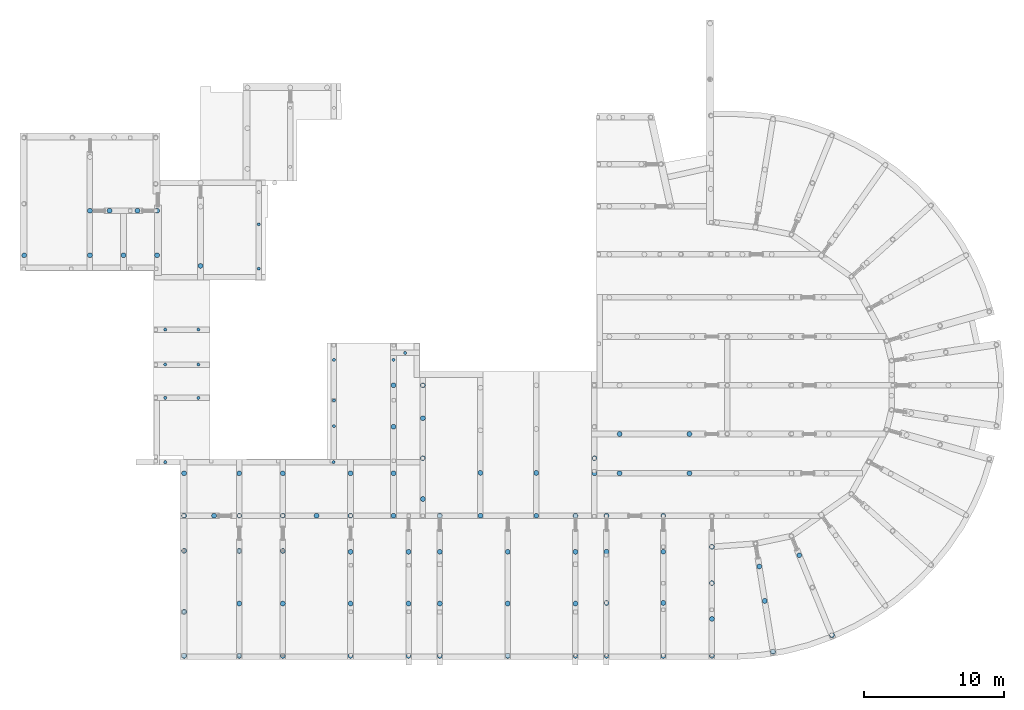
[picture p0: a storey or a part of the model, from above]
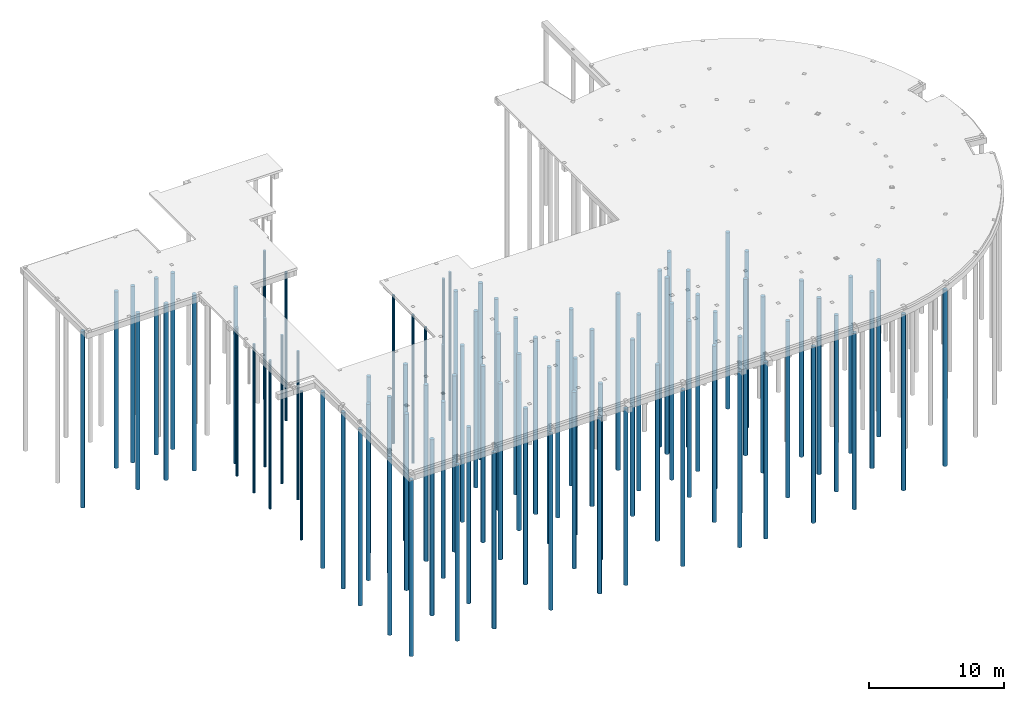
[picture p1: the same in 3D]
Properties of the parts of a building model (IFC2X3)

# File
Description: ViewDefinition[CoordinationView_V2.0, QuantityTakeOffAddOnView], Option [BaseQuantities:On], Option [GridExport:Off], Option [Assemblies:Off], Option [Bolts:On], Option [Rebars:On], Option [PourObjects:Off], Option [Welds:On], Option [SurfaceTreatments:On], Option [LocationBy:0], Option [ViewColors:On], Option [SectionedSpine:Off], Option [PropertySets:On], Option [Export all:Off]
File name: 8694 IFC Fundering revA 17-03-2023.ifc
Time: 2023-03-17T07:30:23
Author: IMJ\s.sijsma
Organization: Structural Designer
Written by: IFC Parser Version: 3.13.2
Made in: Tekla Structures 2022 Service Pack 4, IFC Export Version: 4.0.0.0 Aug 24 2022

# IfcProject, Undefined
BIM Basis ILS - IFC_BUILDING_STOREY: Undefined

# IfcBuildingStorey, Undefined
In: Undefined
Elevation: 0 mm

# IfcBeam: 400*500 (79)
In: Undefined
Description: 400*500; Material: CONCRETE/C30/37
BIM Basis ILS - IS_EXTERNAL: Nee; LOAD_BEARING: Nee; IFC_ENTITY: Auto
Default - MATERIAL: C30/37; NAME: BALK
Tekla Common - Bottom elevation: -0.770; Top elevation: -0.270; Phase: 200; Class: 8
Tekla Quantity - Height: 500 mm; Width: 400 mm
Pset_BeamCommon - IsExternal: no; LoadBearing: no; Reference: BB00(?)
Name | Weight (kg) | Volume (m3) | Gross footprint area (m2) | Area per tons (m2) | Net surface area (m2) | Tekla Quantity, Length (mm) | BaseQuantities, Length (mm) | OuterSurfaceArea (m2) | NetVolume (m3) | NetWeight (kg)
BALK | 2401.81 | 1.001 | 2.002 | 3.917 | 9.407 | 5003.8 | 5003.77 | 9.40679 | 1.00075 | 2401.81
BALK | 3215.83 | 1.34 | 2.68 | 3.874 | 12.459 | 6699.6 | 6699.64 | 12.4594 | 1.33993 | 3215.83
BALK | 2153.51 | 0.897 | 1.795 | 3.936 | 8.476 | 4486.5 | 4486.47 | 8.47565 | 0.897294 | 2153.51
2 x BALK | 816.33 | 0.34 | 0.68 | 4.241 | 3.462 | 1725.6 | 1725.63 | 3.46203 | 0.340139 | 816.334
BALK | 11942.2 | 4.976 | 9.952 | 3.784 | 45.184 | 24886.4 | 24886.4 | 45.1835 | 4.97594 | 11942.2
BALK | 12793 | 5.33 | 10.661 | 3.781 | 48.374 | 26658.8 | 26658.8 | 48.3738 | 5.33041 | 12793
BALK | 1714.9 | 0.715 | 1.429 | 3.983 | 6.831 | 3572.7 | 3572.71 | 6.83088 | 0.714542 | 1714.9
BALK | 2044.02 | 0.852 | 1.703 | 3.946 | 8.065 | 4258.4 | 4258.38 | 8.06508 | 0.851676 | 2044.02
BALK | 7235.25 | 3.015 | 6.029 | 3.805 | 27.532 | 15073.4 | 15073.4 | 27.5322 | 3.01469 | 7235.25
BALK | 7056.49 | 2.94 | 5.88 | 3.807 | 26.862 | 14701 | 14701 | 26.8618 | 2.94021 | 7056.49
BALK | 2963.76 | 1.235 | 2.47 | 3.885 | 11.514 | 6174.5 | 6174.49 | 11.5141 | 1.2349 | 2963.76
2 x BALK | 2963.56 | 1.235 | 2.47 | 3.885 | 11.513 | 6174.1 | 6174.09 | 11.5134 | 1.23482 | 2963.56
BALK | 5294.5 | 2.206 | 4.412 | 3.826 | 20.254 | 11030.2 | 11030.2 | 20.2544 | 2.20604 | 5294.5
2 x BALK | 3940.48 | 1.642 | 3.284 | 3.852 | 15.177 | 8209.3 | 8209.33 | 15.1768 | 1.64187 | 3940.48
BALK | 3761.73 | 1.567 | 3.135 | 3.856 | 14.506 | 7836.9 | 7836.94 | 14.5065 | 1.56739 | 3761.73
BALK | 3542.72 | 1.476 | 2.952 | 3.863 | 13.685 | 7380.7 | 7380.67 | 13.6852 | 1.47613 | 3542.72
BALK | 6171.96 | 2.572 | 5.143 | 3.815 | 23.545 | 12858.3 | 12858.3 | 23.5449 | 2.57165 | 6171.96
BALK | 2832.2 | 1.18 | 2.36 | 3.891 | 11.021 | 5900.4 | 5900.41 | 11.0207 | 1.18008 | 2832.2
3 x BALK | 2345.29 | 0.977 | 1.954 | 3.921 | 9.195 | 4886 | 4886.02 | 9.19483 | 0.977203 | 2345.29
BALK | 13706 | 5.711 | 11.422 | 3.779 | 51.798 | 28554.2 | 28554.2 | 51.7975 | 5.71083 | 13706
BALK | 1347.88 | 0.562 | 1.123 | 4.047 | 5.455 | 2808.1 | 2808.08 | 5.45454 | 0.561616 | 1347.88
BALK | 996.89 | 0.415 | 0.831 | 4.151 | 4.138 | 2076.9 | 2076.85 | 4.13834 | 0.415371 | 996.89
BALK | 1166.15 | 0.486 | 0.972 | 4.093 | 4.773 | 2429.5 | 2429.48 | 4.77306 | 0.485895 | 1166.15
BALK | 2363.52 | 0.985 | 1.97 | 3.919 | 9.263 | 4924 | 4923.99 | 9.26318 | 0.984798 | 2363.52
BALK | 4097.51 | 1.707 | 3.415 | 3.848 | 15.766 | 8536.5 | 8536.47 | 15.7656 | 1.70729 | 4097.51
BALK | 1230.9 | 0.513 | 1.026 | 4.075 | 5.016 | 2564.4 | 2564.37 | 5.01586 | 0.512873 | 1230.9
BALK | 2724.78 | 1.135 | 2.271 | 3.897 | 10.618 | 5676.6 | 5676.62 | 10.6179 | 1.13532 | 2724.78
BALK | 4855.85 | 2.023 | 4.047 | 3.832 | 18.609 | 10116.4 | 10116.4 | 18.6094 | 2.02327 | 4855.85
BALK | 3869.92 | 1.612 | 3.225 | 3.853 | 14.912 | 8062.3 | 8062.34 | 14.9122 | 1.61247 | 3869.92
BALK | 3399.12 | 1.416 | 2.833 | 3.868 | 13.147 | 7081.5 | 7081.51 | 13.1467 | 1.4163 | 3399.12
BALK | 2856.74 | 1.19 | 2.381 | 3.891 | 11.113 | 5951.5 | 5951.53 | 11.1128 | 1.19031 | 2856.74
BALK | 3815.86 | 1.59 | 3.18 | 3.856 | 14.709 | 7949.7 | 7949.72 | 14.7095 | 1.58994 | 3815.86
2 x BALK | 1905.59 | 0.794 | 1.588 | 3.96 | 7.546 | 3970 | 3969.97 | 7.54595 | 0.793994 | 1905.59
BALK | 1908.71 | 0.795 | 1.591 | 3.96 | 7.558 | 3976.5 | 3976.47 | 7.55765 | 0.795294 | 1908.71
BALK | 9965.13 | 4.152 | 8.304 | 3.79 | 37.769 | 20760.7 | 20760.7 | 37.7693 | 4.15214 | 9965.13
BALK | 3988.27 | 1.662 | 3.324 | 3.85 | 15.356 | 8308.9 | 8308.89 | 15.356 | 1.66178 | 3988.27
4 x BALK | 5046.09 | 2.103 | 4.205 | 3.829 | 19.323 | 10512.7 | 10512.7 | 19.3229 | 2.10254 | 5046.09
BALK | 1463.89 | 0.61 | 1.22 | 4.026 | 5.893 | 3093.8 | 3093.84 | 5.89298 | 0.609954 | 1463.89
BALK | 6020.23 | 2.508 | 5.017 | 3.816 | 22.976 | 12542.2 | 12542.2 | 22.9759 | 2.50843 | 6020.23
BALK | 1111.32 | 0.463 | 0.926 | 4.114 | 4.572 | 2359.6 | 2359.62 | 4.57231 | 0.463049 | 1111.32
BALK | 2148.03 | 0.895 | 1.79 | 4.005 | 8.602 | 4758.6 | 4758.62 | 8.6021 | 0.895011 | 2148.03
BALK | 1700.73 | 0.709 | 1.417 | 3.985 | 6.778 | 3543.2 | 3543.19 | 6.77774 | 0.708638 | 1700.73
BALK | 2443.09 | 1.018 | 2.036 | 3.914 | 9.562 | 5089.8 | 5089.78 | 9.5616 | 1.01796 | 2443.09
BALK | 1697.58 | 0.707 | 1.415 | 3.986 | 6.766 | 3536.6 | 3536.62 | 6.76592 | 0.707324 | 1697.58
BALK | 2444.65 | 1.019 | 2.036 | 3.914 | 9.567 | 5093 | 5093.01 | 9.56742 | 1.0186 | 2444.65
BALK | 1355.99 | 0.565 | 1.13 | 4.045 | 5.485 | 2825 | 2824.99 | 5.48498 | 0.564998 | 1355.99
BALK | 18977.9 | 7.907 | 15.815 | 3.771 | 71.569 | 39576.1 | 39576.1 | 71.569 | 7.90745 | 18977.9
BALK | 3254.38 | 1.356 | 2.712 | 3.874 | 12.604 | 6779.9 | 6779.95 | 12.6039 | 1.35599 | 3254.38
BALK | 3158.23 | 1.316 | 2.632 | 3.877 | 12.243 | 6579.7 | 6579.65 | 12.2434 | 1.31593 | 3158.23
BALK | 3302 | 1.376 | 2.752 | 3.871 | 12.783 | 6879.2 | 6879.18 | 12.7825 | 1.37584 | 3302
BALK | 3158.27 | 1.316 | 2.632 | 3.877 | 12.243 | 6579.7 | 6579.73 | 12.2435 | 1.31595 | 3158.27
BALK | 3302.36 | 1.376 | 2.752 | 3.871 | 12.784 | 6879.9 | 6879.91 | 12.7838 | 1.37598 | 3302.36
BALK | 3106.88 | 1.295 | 2.589 | 3.879 | 12.051 | 6472.7 | 6472.68 | 12.0508 | 1.29454 | 3106.88
BALK | 3302.52 | 1.376 | 2.752 | 3.871 | 12.784 | 6880.3 | 6880.25 | 12.7845 | 1.37605 | 3302.52
BALK | 3159.9 | 1.316 | 2.632 | 3.877 | 12.25 | 6583.1 | 6583.13 | 12.2496 | 1.31663 | 3159.9
BALK | 3303.78 | 1.376 | 2.752 | 3.871 | 12.789 | 6882.9 | 6882.87 | 12.7892 | 1.37657 | 3303.78
BALK | 3321.67 | 1.384 | 2.768 | 3.871 | 12.856 | 6920.2 | 6920.15 | 12.8563 | 1.38403 | 3321.67
BALK | 3401.18 | 1.417 | 2.833 | 3.868 | 13.154 | 7085.8 | 7085.78 | 13.1544 | 1.41716 | 3401.18
3 x BALK | 4458 | 1.858 | 3.715 | 3.84 | 17.118 | 9287.5 | 9287.5 | 17.1175 | 1.8575 | 4458
4 x BALK | 4654.83 | 1.94 | 3.879 | 3.836 | 17.856 | 9697.6 | 9697.56 | 17.8556 | 1.93951 | 4654.83
3 x BALK | 4146.07 | 1.728 | 3.455 | 3.846 | 15.948 | 8637.7 | 8637.65 | 15.9478 | 1.72753 | 4146.07
BALK | 3080.63 | 1.284 | 2.567 | 3.879 | 11.953 | 6431.8 | 6431.81 | 11.9526 | 1.2836 | 3080.63
BALK | 19172.1 | 7.988 | 15.977 | 3.771 | 72.295 | 39941.9 | 39941.9 | 72.2954 | 7.98838 | 19172.1

# IfcBeam: 500*500 (14)
In: Undefined
Description: 500*500; Material: CONCRETE/C30/37
BIM Basis ILS - IS_EXTERNAL: Nee; LOAD_BEARING: Nee; IFC_ENTITY: Auto
Default - MATERIAL: C30/37; NAME: BALK
Pset_BeamCommon - IsExternal: no; LoadBearing: no; Reference: BB00(?)
Tekla Common - Bottom elevation: -0.770; Top elevation: -0.270; Phase: 200
Tekla Quantity - Height: 500 mm; Width: 500 mm
Name | Class | Weight (kg) = NetWeight (kg) | Volume (m3) | Gross footprint area (m2) | Area per tons (m2) | Net surface area (m2) | Tekla Quantity, Length (mm) | BaseQuantities, Length (mm) | OuterSurfaceArea (m2) | NetVolume (m3)
BALK | 9 | 4166.64 | 1.736 | 3.472 | 3.453 | 14.389 | 6949.5 | 6949.53 | 14.3889 | 1.7361
BALK | 9 | 4165.25 | 1.736 | 3.472 | 3.453 | 14.385 | 6956.4 | 6956.38 | 14.3846 | 1.73552
BALK | 7 | 4134.61 | 1.723 | 3.446 | 3.453 | 14.282 | 6891.2 | 6891.22 | 14.282 | 1.72275
BALK | 9 | 2610 | 1.087 | 2.175 | 3.525 | 9.2 | 4350 | 4350 | 9.2 | 1.0875
BALK | 9 | 5904.02 | 2.46 | 4.92 | 3.418 | 20.18 | 9840 | 9840.04 | 20.1801 | 2.46001
BALK | 9 | 6009.71 | 2.504 | 5.008 | 3.418 | 20.532 | 10016.2 | 10016.2 | 20.5324 | 2.50404
BALK | 9 | 4194.96 | 1.748 | 3.496 | 3.453 | 14.483 | 6991.6 | 6991.6 | 14.4832 | 1.7479
BALK | 9 | 4392.99 | 1.83 | 3.661 | 3.447 | 15.143 | 7321.6 | 7321.65 | 15.1433 | 1.83041
BALK | 9 | 3011.88 | 1.255 | 2.51 | 3.499 | 10.54 | 5019.8 | 5019.8 | 10.5396 | 1.25495
BALK | 9 | 3910.98 | 1.63 | 3.259 | 3.464 | 13.549 | 6629.3 | 6629.32 | 13.5488 | 1.62957
BALK | 9 | 8790.99 | 3.663 | 7.326 | 3.39 | 29.805 | 14681.8 | 14681.8 | 29.8051 | 3.66291
BALK | 9 | 2474.62 | 1.031 | 2.062 | 3.538 | 8.755 | 4179.9 | 4179.88 | 8.75482 | 1.03109
BALK | 9 | 8594.2 | 3.581 | 7.162 | 3.392 | 29.147 | 14323.7 | 14323.7 | 29.1473 | 3.58092
BALK | 7 | 4139.8 | 1.725 | 3.45 | 3.453 | 14.3 | 6908.5 | 6908.53 | 14.2995 | 1.72492

# IfcBeam: ANKER_M16 (52)
In: Undefined
Description: ANKER_M16; Material: STEEL/S235JR
Default - MATERIAL: S235JR; NAME: ANKER
BIM Basis ILS - IS_EXTERNAL: Nee; LOAD_BEARING: Nee; IFC_ENTITY: Auto
Tekla Common - Phase: 230; Class: 1
Tekla Quantity - Volume: 0 m3; Gross footprint area: 0 m2; Height: 16 mm; Width: 16 mm
Pset_BeamCommon - IsExternal: no; LoadBearing: no; Reference: P0(?)
Name | Bottom elevation | Top elevation | Weight (kg) | Area per tons (m2) | Net surface area (m2) | Tekla Quantity, Length (mm) | BaseQuantities, Length (mm) | OuterSurfaceArea (m2) | NetVolume (m3) | NetWeight (kg)
16 x ANKER | -0.400 | +0.000 | 0.61 | 35.09 | 0.022 | 432.1 | 432.128 | 0.021501 | 0.0000780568 | 0.612746
4 x ANKER | -0.600 | -0.200 | 0.61 | 35.09 | 0.022 | 432.1 | 432.128 | 0.021501 | 0.0000780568 | 0.612746
28 x ANKER | -0.508 | +0.000 | 0.77 | 34.966 | 0.027 | 540.1 | 540.128 | 0.0267912 | 0.0000976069 | 0.766214
4 x ANKER | -0.420 | -0.020 | 0.61 | 35.09 | 0.022 | 432.1 | 432.128 | 0.021501 | 0.0000780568 | 0.612746

# IfcBeam: L150/100/10 (88)
In: Undefined
Description: L150/100/10; Material: STEEL/S235JR
BIM Basis ILS - IS_EXTERNAL: Nee; LOAD_BEARING: Nee; IFC_ENTITY: Auto
Default - MATERIAL: S235JR; NAME: Ligger
Tekla Common - Bottom elevation: -0.280; Top elevation: -0.130; Class: 6
Tekla Quantity - Weight: 18.84 kg; Volume: 0.002 m3; Gross footprint area: 0.01 m2; Area per tons: 26.539 m2; Net surface area: 0.505 m2; Height: 150 mm; Width: 100 mm; Length: 1000 mm
Pset_BeamCommon - IsExternal: no; LoadBearing: no; Reference: L0(?)
BaseQuantities - Length: 1000 mm; OuterSurfaceArea: 0.5 m2; NetVolume: 0.0024 m3; NetWeight: 18.84 kg
Name | Phase
5 x Ligger | 2
83 x Ligger | 210

# IfcColumn: 250*250 (111)
In: Undefined
Description: 250*250; Material: CONCRETE/C30/37
BIM Basis ILS - IS_EXTERNAL: Nee; LOAD_BEARING: Nee; IFC_ENTITY: Auto
Default - MATERIAL: C30/37; NAME: Opstort
Tekla Common - Phase: 230; Class: 8
Tekla Quantity - Weight: 30 kg; Area per tons: 10.833 m2; Net surface area: 0.325 m2; Height: 250 mm; Width: 250 mm; Length: 200 mm
Pset_ColumnCommon - IsExternal: no; LoadBearing: no; Reference: KB0(?)
BaseQuantities - Length: 200 mm; OuterSurfaceArea: 0.325 m2; NetVolume: 0.0125 m3; NetWeight: 30 kg
Name | Bottom elevation | Top elevation | Volume (m3) | Gross footprint area (m2)
93 x Opstort | -0.270 | -0.070 | 0.013 | 0.063
9 x Opstort | -0.270 | -0.070 | 0.012 | 0.062
9 x Opstort | -0.290 | -0.090 | 0.013 | 0.063

# IfcColumn: 300*300 (20)
In: Undefined
Description: 300*300; Material: CONCRETE/C30/37
BIM Basis ILS - IS_EXTERNAL: Nee; LOAD_BEARING: Nee; IFC_ENTITY: Auto
Default - MATERIAL: C30/37; NAME: Opstort
Tekla Common - Bottom elevation: -0.270; Top elevation: -0.070; Phase: 230; Class: 8
Pset_ColumnCommon - IsExternal: no; LoadBearing: no; Reference: KB0(?)
Tekla Quantity - Weight: 43.2 kg; Volume: 0.018 m3; Gross footprint area: 0.09 m2; Area per tons: 9.722 m2; Net surface area: 0.42 m2; Height: 300 mm; Width: 300 mm; Length: 200 mm
BaseQuantities - Length: 200 mm; OuterSurfaceArea: 0.42 m2; NetVolume: 0.018 m3; NetWeight: 43.2 kg

# IfcColumn: 350*350 (6)
In: Undefined
Description: 350*350; Material: CONCRETE/C30/37
BIM Basis ILS - IS_EXTERNAL: Nee; LOAD_BEARING: Nee; IFC_ENTITY: Auto
Default - MATERIAL: C30/37; NAME: Opstort
Tekla Common - Bottom elevation: -0.270; Top elevation: -0.070; Phase: 230; Class: 8
Pset_ColumnCommon - IsExternal: no; LoadBearing: no; Reference: KB0(?)
Tekla Quantity - Weight: 58.8 kg; Area per tons: 8.929 m2; Net surface area: 0.525 m2; Height: 350 mm; Width: 350 mm; Length: 200 mm
BaseQuantities - Length: 200 mm; OuterSurfaceArea: 0.525 m2; NetVolume: 0.0245 m3; NetWeight: 58.8 kg
Name | Volume (m3) | Gross footprint area (m2)
4 x Opstort | 0.025 | 0.123
2 x Opstort | 0.024 | 0.122

# IfcMechanicalFastener: Bolt assembly (13)
In: Undefined
NominalDiameter: 16 mm; NominalLength: 15 mm; Material: Undefined
BIM Basis ILS - IS_EXTERNAL: Nee; LOAD_BEARING: Nee; IFC_ENTITY: Auto
Tekla Bolt - Phase: 230; Washer count: 0; Washer diameter: 16 mm; Washer type: 7089; Washer name: RING-M16-7089; Nut count: 0; Nut type: 4032; Nut name: MOER-M16-4032; Slotted hole y: 0 mm; Slotted hole x: 0 mm; Bolt hole diameter: 20 mm; Location: Montage; Bolt count: 4; Bolt size: 20 mm; Bolt length: 15 mm; Bolt standard: 4014-8.8; Bolt Name: BOUT

# IfcPile (223)
In: Undefined
Material: CONCRETE/C28/35(prefab)
BIM Basis ILS - IS_EXTERNAL: Nee; LOAD_BEARING: Nee; IFC_ENTITY: Auto
Default - MATERIAL: C28/35(prefab); NAME: FUNDERINGSPAAL
Tekla Common - Top elevation: -0.770; Class: 99
Name | Description | ACN | Bottom elevation | Phase | Weight (kg) = NetWeight (kg) = GrossWeight (kg) | Volume (m3) | Gross footprint area (m2) | Area per tons (m2) | Net surface area (m2) | Height (mm) = Width (mm) | Tekla Quantity, Length (mm) = BaseQuantities, Length (mm) | OuterSurfaceArea (m2) = GrossSurfaceArea (m2) | CrossSectionArea (m2) | NetVolume (m3) = GrossVolume (m3)
FUNDERINGSPAAL | D350 | 141 | -16.670 | 100 | 3799.87 | 1.52 | 0.096 | 4.644 | 17.646 | 350 | 15900 | 17.6461 | 0.0955943 | 1.51995
FUNDERINGSPAAL | D350 | 37 | -16.670 | 100 | 3799.87 | 1.52 | 0.096 | 4.644 | 17.646 | 350 | 15900 | 17.6461 | 0.0955943 | 1.51995
FUNDERINGSPAAL | D350 | 30 | -16.670 | 100 | 3799.87 | 1.52 | 0.096 | 4.644 | 17.646 | 350 | 15900 | 17.6461 | 0.0955943 | 1.51995
FUNDERINGSPAAL | D350 | 149 | -16.670 | 100 | 3799.87 | 1.52 | 0.096 | 4.644 | 17.646 | 350 | 15900 | 17.6461 | 0.0955943 | 1.51995
FUNDERINGSPAAL | D350 | 96 | -16.670 | 100 | 3799.87 | 1.52 | 0.096 | 4.644 | 17.646 | 350 | 15900 | 17.6461 | 0.0955943 | 1.51995
FUNDERINGSPAAL | D350 | 113 | -16.670 | 100 | 3799.87 | 1.52 | 0.096 | 4.644 | 17.646 | 350 | 15900 | 17.6461 | 0.0955943 | 1.51995
FUNDERINGSPAAL | D350 | 150 | -16.670 | 100 | 3799.87 | 1.52 | 0.096 | 4.644 | 17.646 | 350 | 15900 | 17.6461 | 0.0955943 | 1.51995
FUNDERINGSPAAL | D350 | 148 | -16.670 | 100 | 3799.87 | 1.52 | 0.096 | 4.644 | 17.646 | 350 | 15900 | 17.6461 | 0.0955943 | 1.51995
FUNDERINGSPAAL | D350 | 31 | -16.670 | 100 | 3799.87 | 1.52 | 0.096 | 4.644 | 17.646 | 350 | 15900 | 17.6461 | 0.0955943 | 1.51995
FUNDERINGSPAAL | D219 | 50 | -14.170 | 100 | 1251.33 | 0.501 | 0.037 | 7.412 | 9.275 | 219 | 13400 | 9.27469 | 0.0373531 | 0.500532
FUNDERINGSPAAL | D219 | 58 | -14.170 | 100 | 1251.33 | 0.501 | 0.037 | 7.412 | 9.275 | 219 | 13400 | 9.27469 | 0.0373531 | 0.500532
FUNDERINGSPAAL | D350 | 10 | -16.670 | 100 | 3799.87 | 1.52 | 0.096 | 4.644 | 17.646 | 350 | 15900 | 17.6461 | 0.0955943 | 1.51995
FUNDERINGSPAAL | D350 | 1 | -16.670 | 100 | 3799.87 | 1.52 | 0.096 | 4.644 | 17.646 | 350 | 15900 | 17.6461 | 0.0955943 | 1.51995
FUNDERINGSPAAL | D350 | 3 | -16.670 | 100 | 3799.87 | 1.52 | 0.096 | 4.644 | 17.646 | 350 | 15900 | 17.6461 | 0.0955943 | 1.51995
FUNDERINGSPAAL | D350 | 2 | -16.670 | 100 | 3799.87 | 1.52 | 0.096 | 4.644 | 17.646 | 350 | 15900 | 17.6461 | 0.0955943 | 1.51995
FUNDERINGSPAAL | D350 | 4 | -16.670 | 100 | 3799.87 | 1.52 | 0.096 | 4.644 | 17.646 | 350 | 15900 | 17.6461 | 0.0955943 | 1.51995
FUNDERINGSPAAL | D350 | 13 | -16.670 | 100 | 3799.87 | 1.52 | 0.096 | 4.644 | 17.646 | 350 | 15900 | 17.6461 | 0.0955943 | 1.51995
FUNDERINGSPAAL | D350 | 9 | -16.670 | 100 | 3799.87 | 1.52 | 0.096 | 4.644 | 17.646 | 350 | 15900 | 17.6461 | 0.0955943 | 1.51995
FUNDERINGSPAAL | D350 | 12 | -16.670 | 100 | 3799.87 | 1.52 | 0.096 | 4.644 | 17.646 | 350 | 15900 | 17.6461 | 0.0955943 | 1.51995
FUNDERINGSPAAL | D350 | 15 | -16.670 | 100 | 3799.87 | 1.52 | 0.096 | 4.644 | 17.646 | 350 | 15900 | 17.6461 | 0.0955943 | 1.51995
FUNDERINGSPAAL | D350 | 14 | -16.670 | 100 | 3799.87 | 1.52 | 0.096 | 4.644 | 17.646 | 350 | 15900 | 17.6461 | 0.0955943 | 1.51995
FUNDERINGSPAAL | D350 | 5 | -16.670 | 100 | 3799.87 | 1.52 | 0.096 | 4.644 | 17.646 | 350 | 15900 | 17.6461 | 0.0955943 | 1.51995
FUNDERINGSPAAL | D350 | 6 | -16.670 | 100 | 3799.87 | 1.52 | 0.096 | 4.644 | 17.646 | 350 | 15900 | 17.6461 | 0.0955943 | 1.51995
FUNDERINGSPAAL | D350 | 7 | -16.670 | 100 | 3799.87 | 1.52 | 0.096 | 4.644 | 17.646 | 350 | 15900 | 17.6461 | 0.0955943 | 1.51995
FUNDERINGSPAAL | D350 | 8 | -16.670 | 100 | 3799.87 | 1.52 | 0.096 | 4.644 | 17.646 | 350 | 15900 | 17.6461 | 0.0955943 | 1.51995
FUNDERINGSPAAL | D350 | 11 | -16.670 | 100 | 3799.87 | 1.52 | 0.096 | 4.644 | 17.646 | 350 | 15900 | 17.6461 | 0.0955943 | 1.51995
FUNDERINGSPAAL | D350 | 28 | -16.670 | 100 | 3799.87 | 1.52 | 0.096 | 4.644 | 17.646 | 350 | 15900 | 17.6461 | 0.0955943 | 1.51995
FUNDERINGSPAAL | D350 | 29 | -16.670 | 100 | 3799.87 | 1.52 | 0.096 | 4.644 | 17.646 | 350 | 15900 | 17.6461 | 0.0955943 | 1.51995
FUNDERINGSPAAL | D350 | 38 | -16.670 | 100 | 3799.87 | 1.52 | 0.096 | 4.644 | 17.646 | 350 | 15900 | 17.6461 | 0.0955943 | 1.51995
FUNDERINGSPAAL | D350 | 39 | -16.670 | 100 | 3799.87 | 1.52 | 0.096 | 4.644 | 17.646 | 350 | 15900 | 17.6461 | 0.0955943 | 1.51995
FUNDERINGSPAAL | D350 | 51 | -16.670 | 100 | 3799.87 | 1.52 | 0.096 | 4.644 | 17.646 | 350 | 15900 | 17.6461 | 0.0955943 | 1.51995
FUNDERINGSPAAL | D219 | 49 | -14.170 | 100 | 1251.33 | 0.501 | 0.037 | 7.412 | 9.275 | 219 | 13400 | 9.27469 | 0.0373531 | 0.500532
FUNDERINGSPAAL | D350 | 53 | -16.670 | 100 | 3799.87 | 1.52 | 0.096 | 4.644 | 17.646 | 350 | 15900 | 17.6461 | 0.0955943 | 1.51995
FUNDERINGSPAAL | D219 | 42 | -14.170 | 100 | 1251.33 | 0.501 | 0.037 | 7.412 | 9.275 | 219 | 13400 | 9.27469 | 0.0373531 | 0.500532
FUNDERINGSPAAL | D219 | 41 | -14.170 | 100 | 1251.33 | 0.501 | 0.037 | 7.412 | 9.275 | 219 | 13400 | 9.27469 | 0.0373531 | 0.500532
FUNDERINGSPAAL | D219 | 40 | -14.170 | 100 | 1251.33 | 0.501 | 0.037 | 7.412 | 9.275 | 219 | 13400 | 9.27469 | 0.0373531 | 0.500532
FUNDERINGSPAAL | D219 | 27 | -14.170 | 100 | 1251.33 | 0.501 | 0.037 | 7.412 | 9.275 | 219 | 13400 | 9.27469 | 0.0373531 | 0.500532
FUNDERINGSPAAL | D219 | 19 | -14.170 | 100 | 1251.33 | 0.501 | 0.037 | 7.412 | 9.275 | 219 | 13400 | 9.27469 | 0.0373531 | 0.500532
FUNDERINGSPAAL | D219 | 26 | -14.170 | 100 | 1251.33 | 0.501 | 0.037 | 7.412 | 9.275 | 219 | 13400 | 9.27469 | 0.0373531 | 0.500532
FUNDERINGSPAAL | D219 | 18 | -14.170 | 100 | 1251.33 | 0.501 | 0.037 | 7.412 | 9.275 | 219 | 13400 | 9.27469 | 0.0373531 | 0.500532
FUNDERINGSPAAL | D219 | 25 | -14.170 | 100 | 1251.33 | 0.501 | 0.037 | 7.412 | 9.275 | 219 | 13400 | 9.27469 | 0.0373531 | 0.500532
FUNDERINGSPAAL | D219 | 17 | -14.170 | 100 | 1251.33 | 0.501 | 0.037 | 7.412 | 9.275 | 219 | 13400 | 9.27469 | 0.0373531 | 0.500532
FUNDERINGSPAAL | D219 | 16 | -14.170 | 100 | 1251.33 | 0.501 | 0.037 | 7.412 | 9.275 | 219 | 13400 | 9.27469 | 0.0373531 | 0.500532
FUNDERINGSPAAL | D350 | 43 | -16.670 | 100 | 3799.87 | 1.52 | 0.096 | 4.644 | 17.646 | 350 | 15900 | 17.6461 | 0.0955943 | 1.51995
FUNDERINGSPAAL | D350 | 21 | -16.670 | 100 | 3799.87 | 1.52 | 0.096 | 4.644 | 17.646 | 350 | 15900 | 17.6461 | 0.0955943 | 1.51995
FUNDERINGSPAAL | D350 | 20 | -16.670 | 100 | 3799.87 | 1.52 | 0.096 | 4.644 | 17.646 | 350 | 15900 | 17.6461 | 0.0955943 | 1.51995
FUNDERINGSPAAL | D350 | 22 | -16.670 | 100 | 3799.87 | 1.52 | 0.096 | 4.644 | 17.646 | 350 | 15900 | 17.6461 | 0.0955943 | 1.51995
FUNDERINGSPAAL | D350 | 23 | -16.670 | 100 | 3799.87 | 1.52 | 0.096 | 4.644 | 17.646 | 350 | 15900 | 17.6461 | 0.0955943 | 1.51995
FUNDERINGSPAAL | D350 | 24 | -16.670 | 100 | 3799.87 | 1.52 | 0.096 | 4.644 | 17.646 | 350 | 15900 | 17.6461 | 0.0955943 | 1.51995
FUNDERINGSPAAL | D350 | 34 | -16.670 | 100 | 3799.87 | 1.52 | 0.096 | 4.644 | 17.646 | 350 | 15900 | 17.6461 | 0.0955943 | 1.51995
FUNDERINGSPAAL | D350 | 46 | -16.670 | 100 | 3799.87 | 1.52 | 0.096 | 4.644 | 17.646 | 350 | 15900 | 17.6461 | 0.0955943 | 1.51995
FUNDERINGSPAAL | D350 | 35 | -16.670 | 100 | 3799.87 | 1.52 | 0.096 | 4.644 | 17.646 | 350 | 15900 | 17.6461 | 0.0955943 | 1.51995
FUNDERINGSPAAL | D350 | 48 | -16.670 | 100 | 3799.87 | 1.52 | 0.096 | 4.644 | 17.646 | 350 | 15900 | 17.6461 | 0.0955943 | 1.51995
FUNDERINGSPAAL | D350 | 63 | -16.670 | 100 | 3799.87 | 1.52 | 0.096 | 4.644 | 17.646 | 350 | 15900 | 17.6461 | 0.0955943 | 1.51995
FUNDERINGSPAAL | D350 | 64 | -16.670 | 100 | 3799.87 | 1.52 | 0.096 | 4.644 | 17.646 | 350 | 15900 | 17.6461 | 0.0955943 | 1.51995
FUNDERINGSPAAL | D350 | 52 | -16.670 | 100 | 3799.87 | 1.52 | 0.096 | 4.644 | 17.646 | 350 | 15900 | 17.6461 | 0.0955943 | 1.51995
FUNDERINGSPAAL | D350 | 60 | -16.670 | 100 | 3799.87 | 1.52 | 0.096 | 4.644 | 17.646 | 350 | 15900 | 17.6461 | 0.0955943 | 1.51995
FUNDERINGSPAAL | D350 | 71 | -16.670 | 100 | 3799.87 | 1.52 | 0.096 | 4.644 | 17.646 | 350 | 15900 | 17.6461 | 0.0955943 | 1.51995
FUNDERINGSPAAL | D350 | 79 | -16.670 | 100 | 3799.87 | 1.52 | 0.096 | 4.644 | 17.646 | 350 | 15900 | 17.6461 | 0.0955943 | 1.51995
FUNDERINGSPAAL | D350 | 45 | -16.670 | 100 | 3799.87 | 1.52 | 0.096 | 4.644 | 17.646 | 350 | 15900 | 17.6461 | 0.0955943 | 1.51995
FUNDERINGSPAAL | D350 | 33 | -16.670 | 100 | 3799.87 | 1.52 | 0.096 | 4.644 | 17.646 | 350 | 15900 | 17.6461 | 0.0955943 | 1.51995
FUNDERINGSPAAL | D350 | 86 | -16.670 | 100 | 3799.87 | 1.52 | 0.096 | 4.644 | 17.646 | 350 | 15900 | 17.6461 | 0.0955943 | 1.51995
FUNDERINGSPAAL | D350 | 94 | -16.670 | 100 | 3799.87 | 1.52 | 0.096 | 4.644 | 17.646 | 350 | 15900 | 17.6461 | 0.0955943 | 1.51995
FUNDERINGSPAAL | D350 | 61 | -16.670 | 100 | 3799.87 | 1.52 | 0.096 | 4.644 | 17.646 | 350 | 15900 | 17.6461 | 0.0955943 | 1.51995
FUNDERINGSPAAL | D350 | 72 | -16.670 | 100 | 3799.87 | 1.52 | 0.096 | 4.644 | 17.646 | 350 | 15900 | 17.6461 | 0.0955943 | 1.51995
FUNDERINGSPAAL | D350 | 78 | -16.670 | 100 | 3799.87 | 1.52 | 0.096 | 4.644 | 17.646 | 350 | 15900 | 17.6461 | 0.0955943 | 1.51995
FUNDERINGSPAAL | D350 | 87 | -16.670 | 100 | 3799.87 | 1.52 | 0.096 | 4.644 | 17.646 | 350 | 15900 | 17.6461 | 0.0955943 | 1.51995
FUNDERINGSPAAL | D350 | 95 | -16.670 | 100 | 3799.87 | 1.52 | 0.096 | 4.644 | 17.646 | 350 | 15900 | 17.6461 | 0.0955943 | 1.51995
FUNDERINGSPAAL | D350 | 32 | -16.670 | 100 | 3799.87 | 1.52 | 0.096 | 4.644 | 17.646 | 350 | 15900 | 17.6461 | 0.0955943 | 1.51995
FUNDERINGSPAAL | D350 | 102 | -16.670 | 100 | 3799.87 | 1.52 | 0.096 | 4.644 | 17.646 | 350 | 15900 | 17.6461 | 0.0955943 | 1.51995
FUNDERINGSPAAL | D350 | 101 | -16.670 | 100 | 3799.87 | 1.52 | 0.096 | 4.644 | 17.646 | 350 | 15900 | 17.6461 | 0.0955943 | 1.51995
FUNDERINGSPAAL | D350 | 120 | -16.670 | 100 | 3799.87 | 1.52 | 0.096 | 4.644 | 17.646 | 350 | 15900 | 17.6461 | 0.0955943 | 1.51995
FUNDERINGSPAAL | D350 | 121 | -16.670 | 100 | 3799.87 | 1.52 | 0.096 | 4.644 | 17.646 | 350 | 15900 | 17.6461 | 0.0955943 | 1.51995
FUNDERINGSPAAL | D350 | 44 | -16.670 | 100 | 3799.87 | 1.52 | 0.096 | 4.644 | 17.646 | 350 | 15900 | 17.6461 | 0.0955943 | 1.51995
FUNDERINGSPAAL | D350 | 59 | -16.670 | 100 | 3799.87 | 1.52 | 0.096 | 4.644 | 17.646 | 350 | 15900 | 17.6461 | 0.0955943 | 1.51995
FUNDERINGSPAAL | D350 | 70 | -16.670 | 100 | 3799.87 | 1.52 | 0.096 | 4.644 | 17.646 | 350 | 15900 | 17.6461 | 0.0955943 | 1.51995
FUNDERINGSPAAL | D350 | 80 | -16.670 | 100 | 3799.87 | 1.52 | 0.096 | 4.644 | 17.646 | 350 | 15900 | 17.6461 | 0.0955943 | 1.51995
FUNDERINGSPAAL | D350 | 85 | -16.670 | 100 | 3799.87 | 1.52 | 0.096 | 4.644 | 17.646 | 350 | 15900 | 17.6461 | 0.0955943 | 1.51995
FUNDERINGSPAAL | D350 | 93 | -16.670 | 100 | 3799.87 | 1.52 | 0.096 | 4.644 | 17.646 | 350 | 15900 | 17.6461 | 0.0955943 | 1.51995
FUNDERINGSPAAL | D350 | 100 | -16.670 | 100 | 3799.87 | 1.52 | 0.096 | 4.644 | 17.646 | 350 | 15900 | 17.6461 | 0.0955943 | 1.51995
FUNDERINGSPAAL | D350 | 119 | -16.670 | 100 | 3799.87 | 1.52 | 0.096 | 4.644 | 17.646 | 350 | 15900 | 17.6461 | 0.0955943 | 1.51995
FUNDERINGSPAAL | D350 | 135 | -16.670 | 100 | 3799.87 | 1.52 | 0.096 | 4.644 | 17.646 | 350 | 15900 | 17.6461 | 0.0955943 | 1.51995
FUNDERINGSPAAL | D350 | 159 | -16.670 | 100 | 3799.87 | 1.52 | 0.096 | 4.644 | 17.646 | 350 | 15900 | 17.6461 | 0.0955943 | 1.51995
FUNDERINGSPAAL | D350 | 180 | -16.670 | 100 | 3799.87 | 1.52 | 0.096 | 4.644 | 17.646 | 350 | 15900 | 17.6461 | 0.0955943 | 1.51995
FUNDERINGSPAAL | D350 | 191 | -16.670 | 100 | 3799.87 | 1.52 | 0.096 | 4.644 | 17.646 | 350 | 15900 | 17.6461 | 0.0955943 | 1.51995
FUNDERINGSPAAL | D350 | 211 | -16.670 | 100 | 3799.87 | 1.52 | 0.096 | 4.644 | 17.646 | 350 | 15900 | 17.6461 | 0.0955943 | 1.51995
FUNDERINGSPAAL | D350 | 218 | -16.670 | 100 | 3799.87 | 1.52 | 0.096 | 4.644 | 17.646 | 350 | 15900 | 17.6461 | 0.0955943 | 1.51995
FUNDERINGSPAAL | D350 | 219 | -16.670 | 100 | 3799.87 | 1.52 | 0.096 | 4.644 | 17.646 | 350 | 15900 | 17.6461 | 0.0955943 | 1.51995
FUNDERINGSPAAL | D350 | 221 | -16.670 | 100 | 3799.87 | 1.52 | 0.096 | 4.644 | 17.646 | 350 | 15900 | 17.6461 | 0.0955943 | 1.51995
FUNDERINGSPAAL | D350 | 223 | -16.670 | 100 | 3799.87 | 1.52 | 0.096 | 4.644 | 17.646 | 350 | 15900 | 17.6461 | 0.0955943 | 1.51995
FUNDERINGSPAAL | D350 | 222 | -16.670 | 100 | 3799.87 | 1.52 | 0.096 | 4.644 | 17.646 | 350 | 15900 | 17.6461 | 0.0955943 | 1.51995
FUNDERINGSPAAL | D350 | 220 | -16.670 | 100 | 3799.87 | 1.52 | 0.096 | 4.644 | 17.646 | 350 | 15900 | 17.6461 | 0.0955943 | 1.51995
FUNDERINGSPAAL | D350 | 217 | -16.670 | 100 | 3799.87 | 1.52 | 0.096 | 4.644 | 17.646 | 350 | 15900 | 17.6461 | 0.0955943 | 1.51995
FUNDERINGSPAAL | D350 | 210 | -16.670 | 100 | 3799.87 | 1.52 | 0.096 | 4.644 | 17.646 | 350 | 15900 | 17.6461 | 0.0955943 | 1.51995
FUNDERINGSPAAL | D350 | 192 | -16.670 | 100 | 3799.87 | 1.52 | 0.096 | 4.644 | 17.646 | 350 | 15900 | 17.6461 | 0.0955943 | 1.51995
FUNDERINGSPAAL | D350 | 179 | -16.670 | 100 | 3799.87 | 1.52 | 0.096 | 4.644 | 17.646 | 350 | 15900 | 17.6461 | 0.0955943 | 1.51995
FUNDERINGSPAAL | D350 | 158 | -16.670 | 100 | 3799.87 | 1.52 | 0.096 | 4.644 | 17.646 | 350 | 15900 | 17.6461 | 0.0955943 | 1.51995
FUNDERINGSPAAL | D350 | 138 | -16.670 | 100 | 3799.87 | 1.52 | 0.096 | 4.644 | 17.646 | 350 | 15900 | 17.6461 | 0.0955943 | 1.51995
FUNDERINGSPAAL | D350 | 137 | -16.670 | 100 | 3799.87 | 1.52 | 0.096 | 4.644 | 17.646 | 350 | 15900 | 17.6461 | 0.0955943 | 1.51995
FUNDERINGSPAAL | D350 | 136 | -16.670 | 100 | 3799.87 | 1.52 | 0.096 | 4.644 | 17.646 | 350 | 15900 | 17.6461 | 0.0955943 | 1.51995
FUNDERINGSPAAL | D350 | 170 | -16.670 | 100 | 3799.87 | 1.52 | 0.096 | 4.644 | 17.646 | 350 | 15900 | 17.6461 | 0.0955943 | 1.51995
FUNDERINGSPAAL | D350 | 201 | -16.670 | 100 | 3799.87 | 1.52 | 0.096 | 4.644 | 17.646 | 350 | 15900 | 17.6461 | 0.0955943 | 1.51995
FUNDERINGSPAAL | D350 | 212 | -16.670 | 100 | 3799.87 | 1.52 | 0.096 | 4.644 | 17.646 | 350 | 15900 | 17.6461 | 0.0955943 | 1.51995
FUNDERINGSPAAL | D350 | 215 | -16.670 | 100 | 3799.87 | 1.52 | 0.096 | 4.644 | 17.646 | 350 | 15900 | 17.6461 | 0.0955943 | 1.51995
FUNDERINGSPAAL | D350 | 214 | -16.670 | 100 | 3799.87 | 1.52 | 0.096 | 4.644 | 17.646 | 350 | 15900 | 17.6461 | 0.0955943 | 1.51995
FUNDERINGSPAAL | D350 | 213 | -16.670 | 100 | 3799.87 | 1.52 | 0.096 | 4.644 | 17.646 | 350 | 15900 | 17.6461 | 0.0955943 | 1.51995
FUNDERINGSPAAL | D350 | 202 | -16.670 | 100 | 3799.87 | 1.52 | 0.096 | 4.644 | 17.646 | 350 | 15900 | 17.6461 | 0.0955943 | 1.51995
FUNDERINGSPAAL | D350 | 171 | -16.670 | 100 | 3799.87 | 1.52 | 0.096 | 4.644 | 17.646 | 350 | 15900 | 17.6461 | 0.0955943 | 1.51995
FUNDERINGSPAAL | D350 | 151 | -16.670 | 100 | 3799.87 | 1.52 | 0.096 | 4.644 | 17.646 | 350 | 15900 | 17.6461 | 0.0955943 | 1.51995
FUNDERINGSPAAL | D350 | 165 | -16.670 | 100 | 3799.87 | 1.52 | 0.096 | 4.644 | 17.646 | 350 | 15900 | 17.6461 | 0.0955943 | 1.51995
FUNDERINGSPAAL | D350 | 172 | -16.670 | 100 | 3799.87 | 1.52 | 0.096 | 4.644 | 17.646 | 350 | 15900 | 17.6461 | 0.0955943 | 1.51995
FUNDERINGSPAAL | D350 | 184 | -16.670 | 100 | 3799.87 | 1.52 | 0.096 | 4.644 | 17.646 | 350 | 15900 | 17.6461 | 0.0955943 | 1.51995
FUNDERINGSPAAL | D350 | 190 | -16.670 | 100 | 3799.87 | 1.52 | 0.096 | 4.644 | 17.646 | 350 | 15900 | 17.6461 | 0.0955943 | 1.51995
FUNDERINGSPAAL | D350 | 193 | -16.670 | 100 | 3799.87 | 1.52 | 0.096 | 4.644 | 17.646 | 350 | 15900 | 17.6461 | 0.0955943 | 1.51995
FUNDERINGSPAAL | D350 | 197 | -16.670 | 100 | 3799.87 | 1.52 | 0.096 | 4.644 | 17.646 | 350 | 15900 | 17.6461 | 0.0955943 | 1.51995
FUNDERINGSPAAL | D350 | 200 | -16.670 | 100 | 3799.87 | 1.52 | 0.096 | 4.644 | 17.646 | 350 | 15900 | 17.6461 | 0.0955943 | 1.51995
FUNDERINGSPAAL | D350 | 194 | -16.670 | 100 | 3799.87 | 1.52 | 0.096 | 4.644 | 17.646 | 350 | 15900 | 17.6461 | 0.0955943 | 1.51995
FUNDERINGSPAAL | D350 | 189 | -16.670 | 100 | 3799.87 | 1.52 | 0.096 | 4.644 | 17.646 | 350 | 15900 | 17.6461 | 0.0955943 | 1.51995
FUNDERINGSPAAL | D350 | 183 | -16.670 | 100 | 3799.87 | 1.52 | 0.096 | 4.644 | 17.646 | 350 | 15900 | 17.6461 | 0.0955943 | 1.51995
FUNDERINGSPAAL | D350 | 173 | -16.670 | 100 | 3799.87 | 1.52 | 0.096 | 4.644 | 17.646 | 350 | 15900 | 17.6461 | 0.0955943 | 1.51995
FUNDERINGSPAAL | D350 | 164 | -16.670 | 100 | 3799.87 | 1.52 | 0.096 | 4.644 | 17.646 | 350 | 15900 | 17.6461 | 0.0955943 | 1.51995
FUNDERINGSPAAL | D350 | 152 | -16.670 | 100 | 3799.87 | 1.52 | 0.096 | 4.644 | 17.646 | 350 | 15900 | 17.6461 | 0.0955943 | 1.51995
FUNDERINGSPAAL | D350 | 198 | -16.670 | 100 | 3799.87 | 1.52 | 0.096 | 4.644 | 17.646 | 350 | 15900 | 17.6461 | 0.0955943 | 1.51995
FUNDERINGSPAAL | D350 | 199 | -16.670 | 100 | 3799.87 | 1.52 | 0.096 | 4.644 | 17.646 | 350 | 15900 | 17.6461 | 0.0955943 | 1.51995
FUNDERINGSPAAL | D350 | 156 | -16.670 | 100 | 3799.87 | 1.52 | 0.096 | 4.644 | 17.646 | 350 | 15900 | 17.6461 | 0.0955943 | 1.51995
FUNDERINGSPAAL | D350 | 154 | -16.670 | 100 | 3799.87 | 1.52 | 0.096 | 4.644 | 17.646 | 350 | 15900 | 17.6461 | 0.0955943 | 1.51995
FUNDERINGSPAAL | D350 | 169 | -16.670 | 100 | 3799.87 | 1.52 | 0.096 | 4.644 | 17.646 | 350 | 15900 | 17.6461 | 0.0955943 | 1.51995
FUNDERINGSPAAL | D350 | 182 | -16.670 | 100 | 3799.87 | 1.52 | 0.096 | 4.644 | 17.646 | 350 | 15900 | 17.6461 | 0.0955943 | 1.51995
FUNDERINGSPAAL | D350 | 186 | -16.670 | 100 | 3799.87 | 1.52 | 0.096 | 4.644 | 17.646 | 350 | 15900 | 17.6461 | 0.0955943 | 1.51995
FUNDERINGSPAAL | D350 | 188 | -16.670 | 100 | 3799.87 | 1.52 | 0.096 | 4.644 | 17.646 | 350 | 15900 | 17.6461 | 0.0955943 | 1.51995
FUNDERINGSPAAL | D350 | 196 | -16.670 | 100 | 3799.87 | 1.52 | 0.096 | 4.644 | 17.646 | 350 | 15900 | 17.6461 | 0.0955943 | 1.51995
FUNDERINGSPAAL | D350 | 209 | -16.670 | 100 | 3799.87 | 1.52 | 0.096 | 4.644 | 17.646 | 350 | 15900 | 17.6461 | 0.0955943 | 1.51995
FUNDERINGSPAAL | D350 | 203 | -16.670 | 100 | 3799.87 | 1.52 | 0.096 | 4.644 | 17.646 | 350 | 15900 | 17.6461 | 0.0955943 | 1.51995
FUNDERINGSPAAL | D350 | 205 | -16.670 | 100 | 3799.87 | 1.52 | 0.096 | 4.644 | 17.646 | 350 | 15900 | 17.6461 | 0.0955943 | 1.51995
FUNDERINGSPAAL | D350 | 207 | -16.670 | 100 | 3799.87 | 1.52 | 0.096 | 4.644 | 17.646 | 350 | 15900 | 17.6461 | 0.0955943 | 1.51995
FUNDERINGSPAAL | D350 | 216 | -16.670 | 100 | 3799.87 | 1.52 | 0.096 | 4.644 | 17.646 | 350 | 15900 | 17.6461 | 0.0955943 | 1.51995
FUNDERINGSPAAL | D350 | 206 | -16.670 | 100 | 3799.87 | 1.52 | 0.096 | 4.644 | 17.646 | 350 | 15900 | 17.6461 | 0.0955943 | 1.51995
FUNDERINGSPAAL | D350 | 204 | -16.670 | 100 | 3799.87 | 1.52 | 0.096 | 4.644 | 17.646 | 350 | 15900 | 17.6461 | 0.0955943 | 1.51995
FUNDERINGSPAAL | D350 | 195 | -16.670 | 100 | 3799.87 | 1.52 | 0.096 | 4.644 | 17.646 | 350 | 15900 | 17.6461 | 0.0955943 | 1.51995
FUNDERINGSPAAL | D350 | 208 | -16.670 | 100 | 3799.87 | 1.52 | 0.096 | 4.644 | 17.646 | 350 | 15900 | 17.6461 | 0.0955943 | 1.51995
FUNDERINGSPAAL | D350 | 187 | -16.670 | 100 | 3799.87 | 1.52 | 0.096 | 4.644 | 17.646 | 350 | 15900 | 17.6461 | 0.0955943 | 1.51995
FUNDERINGSPAAL | D350 | 181 | -16.670 | 100 | 3799.87 | 1.52 | 0.096 | 4.644 | 17.646 | 350 | 15900 | 17.6461 | 0.0955943 | 1.51995
FUNDERINGSPAAL | D350 | 185 | -16.670 | 100 | 3799.87 | 1.52 | 0.096 | 4.644 | 17.646 | 350 | 15900 | 17.6461 | 0.0955943 | 1.51995
FUNDERINGSPAAL | D350 | 168 | -16.670 | 100 | 3799.87 | 1.52 | 0.096 | 4.644 | 17.646 | 350 | 15900 | 17.6461 | 0.0955943 | 1.51995
FUNDERINGSPAAL | D350 | 155 | -16.670 | 100 | 3799.87 | 1.52 | 0.096 | 4.644 | 17.646 | 350 | 15900 | 17.6461 | 0.0955943 | 1.51995
FUNDERINGSPAAL | D350 | 153 | -16.670 | 100 | 3799.87 | 1.52 | 0.096 | 4.644 | 17.646 | 350 | 15900 | 17.6461 | 0.0955943 | 1.51995
FUNDERINGSPAAL | D350 | 77 | -16.670 | 100 | 3799.87 | 1.52 | 0.096 | 4.644 | 17.646 | 350 | 15900 | 17.6461 | 0.0955943 | 1.51995
FUNDERINGSPAAL | D350 | 88 | -16.670 | 100 | 3799.87 | 1.52 | 0.096 | 4.644 | 17.646 | 350 | 15900 | 17.6461 | 0.0955943 | 1.51995
FUNDERINGSPAAL | D350 | 92 | -16.670 | 100 | 3799.87 | 1.52 | 0.096 | 4.644 | 17.646 | 350 | 15900 | 17.6461 | 0.0955943 | 1.51995
FUNDERINGSPAAL | D350 | 103 | -16.670 | 100 | 3799.87 | 1.52 | 0.096 | 4.644 | 17.646 | 350 | 15900 | 17.6461 | 0.0955943 | 1.51995
FUNDERINGSPAAL | D350 | 122 | -16.670 | 100 | 3799.87 | 1.52 | 0.096 | 4.644 | 17.646 | 350 | 15900 | 17.6461 | 0.0955943 | 1.51995
FUNDERINGSPAAL | D350 | 139 | -16.670 | 100 | 3799.87 | 1.52 | 0.096 | 4.644 | 17.646 | 350 | 15900 | 17.6461 | 0.0955943 | 1.51995
FUNDERINGSPAAL | D350 | 157 | -16.670 | 100 | 3799.87 | 1.52 | 0.096 | 4.644 | 17.646 | 350 | 15900 | 17.6461 | 0.0955943 | 1.51995
FUNDERINGSPAAL | D219 | 56 | -14.170 | 100 | 1251.33 | 0.501 | 0.037 | 7.412 | 9.275 | 219 | 13400 | 9.27469 | 0.0373531 | 0.500532
FUNDERINGSPAAL | D219 | 54 | -14.170 | 100 | 1251.33 | 0.501 | 0.037 | 7.412 | 9.275 | 219 | 13400 | 9.27469 | 0.0373531 | 0.500532
FUNDERINGSPAAL | D350 | 36 | -16.670 | 100 | 3799.87 | 1.52 | 0.096 | 4.644 | 17.646 | 350 | 15900 | 17.6461 | 0.0955943 | 1.51995
FUNDERINGSPAAL | D350 | 62 | -16.670 | 100 | 3799.87 | 1.52 | 0.096 | 4.644 | 17.646 | 350 | 15900 | 17.6461 | 0.0955943 | 1.51995
FUNDERINGSPAAL | D350 | 65 | -16.670 | 100 | 3799.87 | 1.52 | 0.096 | 4.644 | 17.646 | 350 | 15900 | 17.6461 | 0.0955943 | 1.51995
FUNDERINGSPAAL | D350 | 47 | -16.670 | 100 | 3799.87 | 1.52 | 0.096 | 4.644 | 17.646 | 350 | 15900 | 17.6461 | 0.0955943 | 1.51995
FUNDERINGSPAAL | D219 | 55 | -14.170 | 100 | 1251.33 | 0.501 | 0.037 | 7.412 | 9.275 | 219 | 13400 | 9.27469 | 0.0373531 | 0.500532
FUNDERINGSPAAL | D219 | 57 | -14.170 | 219 | 1251.33 | 0.501 | 0.037 | 7.412 | 9.275 | 219 | 13400 | 9.27469 | 0.0373531 | 0.500532
FUNDERINGSPAAL | D219 | 68 | -14.170 | 100 | 1251.33 | 0.501 | 0.037 | 7.412 | 9.275 | 219 | 13400 | 9.27469 | 0.0373531 | 0.500532
FUNDERINGSPAAL | D219 | 69 | -14.170 | 100 | 1251.33 | 0.501 | 0.037 | 7.412 | 9.275 | 219 | 13400 | 9.27469 | 0.0373531 | 0.500532
FUNDERINGSPAAL | D350 | 67 | -16.670 | 100 | 3799.87 | 1.52 | 0.096 | 4.644 | 17.646 | 350 | 15900 | 17.6461 | 0.0955943 | 1.51995
FUNDERINGSPAAL | D350 | 66 | -16.670 | 100 | 3799.87 | 1.52 | 0.096 | 4.644 | 17.646 | 350 | 15900 | 17.6461 | 0.0955943 | 1.51995
FUNDERINGSPAAL | D350 | 76 | -16.670 | 100 | 3799.87 | 1.52 | 0.096 | 4.644 | 17.646 | 350 | 15900 | 17.6461 | 0.0955943 | 1.51995
FUNDERINGSPAAL | D350 | 74 | -16.670 | 100 | 3799.87 | 1.52 | 0.096 | 4.644 | 17.646 | 350 | 15900 | 17.6461 | 0.0955943 | 1.51995
FUNDERINGSPAAL | D350 | 75 | -16.670 | 100 | 3799.87 | 1.52 | 0.096 | 4.644 | 17.646 | 350 | 15900 | 17.6461 | 0.0955943 | 1.51995
FUNDERINGSPAAL | D350 | 73 | -16.670 | 100 | 3799.87 | 1.52 | 0.096 | 4.644 | 17.646 | 350 | 15900 | 17.6461 | 0.0955943 | 1.51995
FUNDERINGSPAAL | D350 | 84 | -16.670 | 100 | 3799.87 | 1.52 | 0.096 | 4.644 | 17.646 | 350 | 15900 | 17.6461 | 0.0955943 | 1.51995
FUNDERINGSPAAL | D350 | 81 | -16.670 | 100 | 3799.87 | 1.52 | 0.096 | 4.644 | 17.646 | 350 | 15900 | 17.6461 | 0.0955943 | 1.51995
FUNDERINGSPAAL | D350 | 89 | -16.670 | 100 | 3799.87 | 1.52 | 0.096 | 4.644 | 17.646 | 350 | 15900 | 17.6461 | 0.0955943 | 1.51995
FUNDERINGSPAAL | D350 | 82 | -16.670 | 100 | 3799.87 | 1.52 | 0.096 | 4.644 | 17.646 | 350 | 15900 | 17.6461 | 0.0955943 | 1.51995
FUNDERINGSPAAL | D350 | 90 | -16.670 | 100 | 3799.87 | 1.52 | 0.096 | 4.644 | 17.646 | 350 | 15900 | 17.6461 | 0.0955943 | 1.51995
FUNDERINGSPAAL | D350 | 83 | -16.670 | 100 | 3799.87 | 1.52 | 0.096 | 4.644 | 17.646 | 350 | 15900 | 17.6461 | 0.0955943 | 1.51995
FUNDERINGSPAAL | D350 | 91 | -16.670 | 100 | 3799.87 | 1.52 | 0.096 | 4.644 | 17.646 | 350 | 15900 | 17.6461 | 0.0955943 | 1.51995
FUNDERINGSPAAL | D350 | 97 | -16.670 | 100 | 3799.87 | 1.52 | 0.096 | 4.644 | 17.646 | 350 | 15900 | 17.6461 | 0.0955943 | 1.51995
FUNDERINGSPAAL | D350 | 98 | -16.670 | 100 | 3799.87 | 1.52 | 0.096 | 4.644 | 17.646 | 350 | 15900 | 17.6461 | 0.0955943 | 1.51995
FUNDERINGSPAAL | D350 | 99 | -16.670 | 100 | 3799.87 | 1.52 | 0.096 | 4.644 | 17.646 | 350 | 15900 | 17.6461 | 0.0955943 | 1.51995
FUNDERINGSPAAL | D350 | 104 | -16.670 | 100 | 3799.87 | 1.52 | 0.096 | 4.644 | 17.646 | 350 | 15900 | 17.6461 | 0.0955943 | 1.51995
FUNDERINGSPAAL | D350 | 105 | -16.670 | 100 | 3799.87 | 1.52 | 0.096 | 4.644 | 17.646 | 350 | 15900 | 17.6461 | 0.0955943 | 1.51995
FUNDERINGSPAAL | D350 | 106 | -16.670 | 100 | 3799.87 | 1.52 | 0.096 | 4.644 | 17.646 | 350 | 15900 | 17.6461 | 0.0955943 | 1.51995
FUNDERINGSPAAL | D350 | 107 | -16.670 | 100 | 3799.87 | 1.52 | 0.096 | 4.644 | 17.646 | 350 | 15900 | 17.6461 | 0.0955943 | 1.51995
FUNDERINGSPAAL | D350 | 108 | -16.670 | 100 | 3799.87 | 1.52 | 0.096 | 4.644 | 17.646 | 350 | 15900 | 17.6461 | 0.0955943 | 1.51995
FUNDERINGSPAAL | D350 | 109 | -16.670 | 100 | 3799.87 | 1.52 | 0.096 | 4.644 | 17.646 | 350 | 15900 | 17.6461 | 0.0955943 | 1.51995
FUNDERINGSPAAL | D350 | 117 | -16.670 | 100 | 3799.87 | 1.52 | 0.096 | 4.644 | 17.646 | 350 | 15900 | 17.6461 | 0.0955943 | 1.51995
FUNDERINGSPAAL | D350 | 118 | -16.670 | 100 | 3799.87 | 1.52 | 0.096 | 4.644 | 17.646 | 350 | 15900 | 17.6461 | 0.0955943 | 1.51995
FUNDERINGSPAAL | D350 | 124 | -16.670 | 100 | 3799.87 | 1.52 | 0.096 | 4.644 | 17.646 | 350 | 15900 | 17.6461 | 0.0955943 | 1.51995
FUNDERINGSPAAL | D350 | 147 | -16.670 | 100 | 3799.87 | 1.52 | 0.096 | 4.644 | 17.646 | 350 | 15900 | 17.6461 | 0.0955943 | 1.51995
FUNDERINGSPAAL | D350 | 167 | -16.670 | 100 | 3799.87 | 1.52 | 0.096 | 4.644 | 17.646 | 350 | 15900 | 17.6461 | 0.0955943 | 1.51995
FUNDERINGSPAAL | D350 | 163 | -16.670 | 100 | 3799.87 | 1.52 | 0.096 | 4.644 | 17.646 | 350 | 15900 | 17.6461 | 0.0955943 | 1.51995
FUNDERINGSPAAL | D350 | 162 | -16.670 | 100 | 3799.87 | 1.52 | 0.096 | 4.644 | 17.646 | 350 | 15900 | 17.6461 | 0.0955943 | 1.51995
FUNDERINGSPAAL | D350 | 161 | -16.670 | 100 | 3799.87 | 1.52 | 0.096 | 4.644 | 17.646 | 350 | 15900 | 17.6461 | 0.0955943 | 1.51995
FUNDERINGSPAAL | D350 | 166 | -16.670 | 100 | 3799.87 | 1.52 | 0.096 | 4.644 | 17.646 | 350 | 15900 | 17.6461 | 0.0955943 | 1.51995
FUNDERINGSPAAL | D350 | 142 | -16.670 | 100 | 3799.87 | 1.52 | 0.096 | 4.644 | 17.646 | 350 | 15900 | 17.6461 | 0.0955943 | 1.51995
FUNDERINGSPAAL | D350 | 143 | -16.670 | 100 | 3799.87 | 1.52 | 0.096 | 4.644 | 17.646 | 350 | 15900 | 17.6461 | 0.0955943 | 1.51995
FUNDERINGSPAAL | D350 | 144 | -16.670 | 100 | 3799.87 | 1.52 | 0.096 | 4.644 | 17.646 | 350 | 15900 | 17.6461 | 0.0955943 | 1.51995
FUNDERINGSPAAL | D350 | 129 | -16.670 | 100 | 3799.87 | 1.52 | 0.096 | 4.644 | 17.646 | 350 | 15900 | 17.6461 | 0.0955943 | 1.51995
FUNDERINGSPAAL | D350 | 128 | -16.670 | 100 | 3799.87 | 1.52 | 0.096 | 4.644 | 17.646 | 350 | 15900 | 17.6461 | 0.0955943 | 1.51995
FUNDERINGSPAAL | D350 | 127 | -16.670 | 100 | 3799.87 | 1.52 | 0.096 | 4.644 | 17.646 | 350 | 15900 | 17.6461 | 0.0955943 | 1.51995
FUNDERINGSPAAL | D350 | 126 | -16.670 | 100 | 3799.87 | 1.52 | 0.096 | 4.644 | 17.646 | 350 | 15900 | 17.6461 | 0.0955943 | 1.51995
FUNDERINGSPAAL | D350 | 175 | -16.670 | 100 | 3799.87 | 1.52 | 0.096 | 4.644 | 17.646 | 350 | 15900 | 17.6461 | 0.0955943 | 1.51995
FUNDERINGSPAAL | D350 | 176 | -16.670 | 100 | 3799.87 | 1.52 | 0.096 | 4.644 | 17.646 | 350 | 15900 | 17.6461 | 0.0955943 | 1.51995
FUNDERINGSPAAL | D350 | 177 | -16.670 | 100 | 3799.87 | 1.52 | 0.096 | 4.644 | 17.646 | 350 | 15900 | 17.6461 | 0.0955943 | 1.51995
FUNDERINGSPAAL | D350 | 178 | -16.670 | 100 | 3799.87 | 1.52 | 0.096 | 4.644 | 17.646 | 350 | 15900 | 17.6461 | 0.0955943 | 1.51995
FUNDERINGSPAAL | D350 | 174 | -16.670 | 100 | 3799.87 | 1.52 | 0.096 | 4.644 | 17.646 | 350 | 15900 | 17.6461 | 0.0955943 | 1.51995
FUNDERINGSPAAL | D350 | 160 | -16.670 | 100 | 3799.87 | 1.52 | 0.096 | 4.644 | 17.646 | 350 | 15900 | 17.6461 | 0.0955943 | 1.51995
FUNDERINGSPAAL | D350 | 123 | -16.670 | 100 | 3799.87 | 1.52 | 0.096 | 4.644 | 17.646 | 350 | 15900 | 17.6461 | 0.0955943 | 1.51995
FUNDERINGSPAAL | D350 | 145 | -16.670 | 100 | 3799.87 | 1.52 | 0.096 | 4.644 | 17.646 | 350 | 15900 | 17.6461 | 0.0955943 | 1.51995
FUNDERINGSPAAL | D350 | 115 | -16.670 | 100 | 3799.87 | 1.52 | 0.096 | 4.644 | 17.646 | 350 | 15900 | 17.6461 | 0.0955943 | 1.51995
FUNDERINGSPAAL | D350 | 114 | -16.670 | 100 | 3799.87 | 1.52 | 0.096 | 4.644 | 17.646 | 350 | 15900 | 17.6461 | 0.0955943 | 1.51995
FUNDERINGSPAAL | D350 | 125 | -16.670 | 100 | 3799.87 | 1.52 | 0.096 | 4.644 | 17.646 | 350 | 15900 | 17.6461 | 0.0955943 | 1.51995
FUNDERINGSPAAL | D350 | 116 | -16.670 | 100 | 3799.87 | 1.52 | 0.096 | 4.644 | 17.646 | 350 | 15900 | 17.6461 | 0.0955943 | 1.51995
FUNDERINGSPAAL | D350 | 140 | -16.670 | 100 | 3799.87 | 1.52 | 0.096 | 4.644 | 17.646 | 350 | 15900 | 17.6461 | 0.0955943 | 1.51995
FUNDERINGSPAAL | D350 | 131 | -16.670 | 100 | 3799.87 | 1.52 | 0.096 | 4.644 | 17.646 | 350 | 15900 | 17.6461 | 0.0955943 | 1.51995
FUNDERINGSPAAL | D350 | 130 | -16.670 | 100 | 3799.87 | 1.52 | 0.096 | 4.644 | 17.646 | 350 | 15900 | 17.6461 | 0.0955943 | 1.51995
FUNDERINGSPAAL | D350 | 134 | -16.670 | 100 | 3799.87 | 1.52 | 0.096 | 4.644 | 17.646 | 350 | 15900 | 17.6461 | 0.0955943 | 1.51995
FUNDERINGSPAAL | D350 | 133 | -16.670 | 100 | 3799.87 | 1.52 | 0.096 | 4.644 | 17.646 | 350 | 15900 | 17.6461 | 0.0955943 | 1.51995
FUNDERINGSPAAL | D350 | 132 | -16.670 | 100 | 3799.87 | 1.52 | 0.096 | 4.644 | 17.646 | 350 | 15900 | 17.6461 | 0.0955943 | 1.51995
FUNDERINGSPAAL | D350 | 112 | -16.670 | 100 | 3799.87 | 1.52 | 0.096 | 4.644 | 17.646 | 350 | 15900 | 17.6461 | 0.0955943 | 1.51995
FUNDERINGSPAAL | D350 | 111 | -16.670 | 100 | 3799.87 | 1.52 | 0.096 | 4.644 | 17.646 | 350 | 15900 | 17.6461 | 0.0955943 | 1.51995
FUNDERINGSPAAL | D350 | 110 | -16.670 | 100 | 3799.87 | 1.52 | 0.096 | 4.644 | 17.646 | 350 | 15900 | 17.6461 | 0.0955943 | 1.51995
FUNDERINGSPAAL | D350 | 146 | -16.670 | 100 | 3799.87 | 1.52 | 0.096 | 4.644 | 17.646 | 350 | 15900 | 17.6461 | 0.0955943 | 1.51995

# IfcPlate: PL15*240 (3)
In: Undefined
Description: PL15*240; Material: STEEL/S235JR
BIM Basis ILS - IS_EXTERNAL: Nee; LOAD_BEARING: Nee; IFC_ENTITY: Auto
Default - MATERIAL: S235JR; NAME: PLAAT
Tekla Common - Bottom elevation: -0.050; Top elevation: -0.035; Phase: 1010; Class: 99
Tekla Quantity - Weight: 6.78 kg; Volume: 0.001 m3; Gross footprint area: 0.058 m2; Area per tons: 19.108 m2; Net surface area: 0.13 m2; Height: 240 mm; Width: 15 mm; Length: 240 mm
Pset_PlateCommon - IsExternal: no; LoadBearing: no; Reference: P0(?)
BaseQuantities - Width: 240 mm; NetArea: 0.1296 m2; GrossArea: 0.1296 m2; CrossSectionArea: 0.0036 m2; NetVolume: 0.000864 m3; GrossVolume: 0.000864 m3

# IfcPlate: STRIP15*140 (4)
In: Undefined
Description: STRIP15*140; Material: STEEL/S235JR
BIM Basis ILS - IS_EXTERNAL: Nee; LOAD_BEARING: Nee; IFC_ENTITY: Auto
Default - MATERIAL: S235JR; NAME: PLAAT
Pset_PlateCommon - IsExternal: no; LoadBearing: no; Reference: P0(?)
Tekla Common - Phase: 1010; Class: 99
Tekla Quantity - Weight: 2.31 kg; Volume: 0 m3; Gross footprint area: 0.02 m2; Area per tons: 20.625 m2; Net surface area: 0.048 m2; Height: 140 mm; Width: 15 mm; Length: 140 mm
BaseQuantities - Width: 140 mm; NetArea: 0.0476 m2; GrossArea: 0.0476 m2; CrossSectionArea: 0.0021 m2; NetVolume: 0.000294 m3; GrossVolume: 0.000294 m3
Name | Bottom elevation | Top elevation
PLAAT | -0.250 | -0.235
3 x PLAAT | -0.050 | -0.035

# IfcPlate: STRIP15*220 (6)
In: Undefined
Description: STRIP15*220; Material: STEEL/S235JR
BIM Basis ILS - IS_EXTERNAL: Nee; LOAD_BEARING: Nee; IFC_ENTITY: Auto
Default - MATERIAL: S235JR; NAME: PLAAT
Tekla Common - Phase: 1010; Class: 99
Pset_PlateCommon - IsExternal: no; LoadBearing: no; Reference: P0(?)
Tekla Quantity - Weight: 5.7 kg; Volume: 0.001 m3; Gross footprint area: 0.048 m2; Area per tons: 19.301 m2; Net surface area: 0.11 m2; Height: 220 mm; Width: 15 mm; Length: 220 mm
BaseQuantities - Width: 220 mm; NetArea: 0.11 m2; GrossArea: 0.11 m2; CrossSectionArea: 0.0033 m2; NetVolume: 0.000726 m3; GrossVolume: 0.000726 m3
Name | Bottom elevation | Top elevation
5 x PLAAT | -0.050 | -0.035
PLAAT | -0.070 | -0.055

# IfcSlab: PL200*40814.3, PS-Isolatievloer
In: Undefined
Description: PL200*40814.3; Material: CONCRETE/C28/35(prefab) 200 mm
BIM Basis ILS - IS_EXTERNAL: Nee; LOAD_BEARING: Nee; IFC_ENTITY: Auto
Default - MATERIAL: C28/35(prefab); NAME: PS-Isolatievloer
Tekla Common - Bottom elevation: -0.270; Top elevation: -0.070; Phase: 400; Class: 2
Tekla Quantity - Weight: 869067 kg; Volume: 347.627 m3; Gross footprint area: 1738.54 m2; Area per tons: 4.095 m2; Net surface area: 3558.63 m2; Height: 40814.3 mm; Width: 200 mm; Length: 70039.4 mm
Pset_SlabCommon - Compartmentation: no; Combustible: no; IsExternal: no; LoadBearing: no; Reference: A0(?)
BaseQuantities - Width: 200 mm; NetVolume: 347.627 m3; NetArea: 1738.54 m2; NetWeight: 869067 kg
